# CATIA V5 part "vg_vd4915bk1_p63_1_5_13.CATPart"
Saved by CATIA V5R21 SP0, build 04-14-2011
Part number: vg_vd4915bk1_p63_1_5_13
Bounding box of the stored display mesh (mm): x -55.3 to 2.5, y -31.441 to 37.158, z -37.158 to 31.441
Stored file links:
  C:\TPO v2\SharedFS\Outgoing\vg_vd4915bk1_p63_1_5_13.CATPart

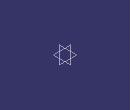
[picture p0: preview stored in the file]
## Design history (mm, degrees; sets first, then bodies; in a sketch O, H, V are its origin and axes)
AxisSystem1: origin (0, 0, 0), X (1, 0, 0), Y (0, 1, 0), Z (0, 0, 1)
Body1 "vg_vd4915bk1_p63_1_5_13" (main body)
  Solid1: solid without history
